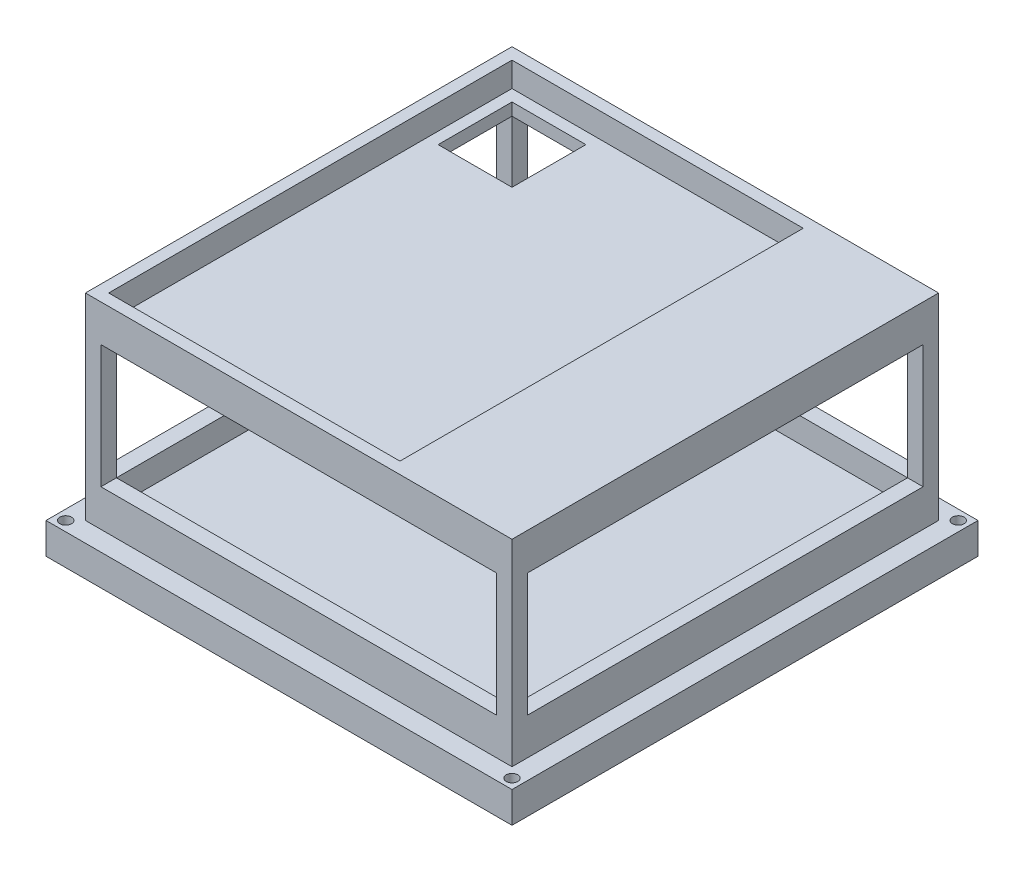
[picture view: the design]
ISO-10303-21;
HEADER;
FILE_DESCRIPTION(('STEP AP214'),'2;1');
FILE_NAME('part.step','',(''),(''),'','','');
FILE_SCHEMA(('AUTOMOTIVE_DESIGN { 1 0 10303 214 1 1 1 1 }'));
ENDSEC;
DATA;
#1=APPLICATION_CONTEXT('core data for automotive mechanical design processes');
#2=APPLICATION_PROTOCOL_DEFINITION('international standard','automotive_design',2000,#1);
#3=PRODUCT_CONTEXT('',#1,'mechanical');
#4=PRODUCT('Part','Part','',(#3));
#5=PRODUCT_RELATED_PRODUCT_CATEGORY('part','',(#4));
#6=PRODUCT_DEFINITION_FORMATION('','',#4);
#7=PRODUCT_DEFINITION_CONTEXT('part definition',#1,'design');
#8=PRODUCT_DEFINITION('design','',#6,#7);
#9=PRODUCT_DEFINITION_SHAPE('','',#8);
#10=(LENGTH_UNIT() NAMED_UNIT(*) SI_UNIT(.MILLI.,.METRE.));
#11=(NAMED_UNIT(*) PLANE_ANGLE_UNIT() SI_UNIT($,.RADIAN.));
#12=(NAMED_UNIT(*) SI_UNIT($,.STERADIAN.) SOLID_ANGLE_UNIT());
#13=UNCERTAINTY_MEASURE_WITH_UNIT(LENGTH_MEASURE(1.E-05),#10,'distance_accuracy_value','');
#14=(GEOMETRIC_REPRESENTATION_CONTEXT(3) GLOBAL_UNCERTAINTY_ASSIGNED_CONTEXT((#13)) GLOBAL_UNIT_ASSIGNED_CONTEXT((#10,
#11,#12)) REPRESENTATION_CONTEXT('',''));
#15=CARTESIAN_POINT('',(0.,0.,0.));
#16=DIRECTION('',(0.,0.,1.));
#17=DIRECTION('',(1.,0.,0.));
#18=AXIS2_PLACEMENT_3D('',#15,#16,#17);
#19=CARTESIAN_POINT('',(0.,9.525,0.));
#20=DIRECTION('',(0.,-1.,0.));
#21=DIRECTION('',(0.,0.,-1.));
#22=AXIS2_PLACEMENT_3D('',#19,#20,#21);
#23=PLANE('',#22);
#24=DIRECTION('',(0.,0.,1.));
#25=VECTOR('',#24,1.);
#26=CARTESIAN_POINT('',(51.,9.525,-55.));
#27=LINE('',#26,#25);
#28=CARTESIAN_POINT('',(51.,9.525,-55.));
#29=VERTEX_POINT('',#28);
#30=CARTESIAN_POINT('',(51.,9.525,-51.));
#31=VERTEX_POINT('',#30);
#32=EDGE_CURVE('E333',#29,#31,#27,.T.);
#33=ORIENTED_EDGE('',*,*,#32,.F.);
#34=DIRECTION('',(-1.,0.,0.));
#35=VECTOR('',#34,1.);
#36=CARTESIAN_POINT('',(-55.,9.525,-55.));
#37=LINE('',#36,#35);
#38=CARTESIAN_POINT('',(-51.,9.525,-55.));
#39=VERTEX_POINT('',#38);
#40=EDGE_CURVE('E497',#29,#39,#37,.T.);
#41=ORIENTED_EDGE('',*,*,#40,.T.);
#42=DIRECTION('',(0.,0.,-1.));
#43=VECTOR('',#42,1.);
#44=CARTESIAN_POINT('',(-51.,9.525,-55.));
#45=LINE('',#44,#43);
#46=CARTESIAN_POINT('',(-51.,9.525,-51.));
#47=VERTEX_POINT('',#46);
#48=EDGE_CURVE('E388',#47,#39,#45,.T.);
#49=ORIENTED_EDGE('',*,*,#48,.F.);
#50=DIRECTION('',(-1.,0.,0.));
#51=VECTOR('',#50,1.);
#52=CARTESIAN_POINT('',(-51.,9.525,-51.));
#53=LINE('',#52,#51);
#54=EDGE_CURVE('E421',#31,#47,#53,.T.);
#55=ORIENTED_EDGE('',*,*,#54,.F.);
#56=EDGE_LOOP('',(#33,#41,#49,#55));
#57=FACE_BOUND('',#56,.T.);
#58=ADVANCED_FACE('F39',(#57),#23,.F.);
#59=DIRECTION('',(1.,0.,0.));
#60=VECTOR('',#59,1.);
#61=CARTESIAN_POINT('',(55.,9.525,-51.));
#62=LINE('',#61,#60);
#63=CARTESIAN_POINT('',(55.,9.525,-51.));
#64=VERTEX_POINT('',#63);
#65=EDGE_CURVE('E330',#31,#64,#62,.T.);
#66=ORIENTED_EDGE('',*,*,#65,.F.);
#67=DIRECTION('',(0.,0.,-1.));
#68=VECTOR('',#67,1.);
#69=CARTESIAN_POINT('',(51.,9.525,51.));
#70=LINE('',#69,#68);
#71=CARTESIAN_POINT('',(51.,9.525,51.));
#72=VERTEX_POINT('',#71);
#73=EDGE_CURVE('E404',#72,#31,#70,.T.);
#74=ORIENTED_EDGE('',*,*,#73,.F.);
#75=DIRECTION('',(-1.,0.,0.));
#76=VECTOR('',#75,1.);
#77=CARTESIAN_POINT('',(55.,9.525,51.));
#78=LINE('',#77,#76);
#79=CARTESIAN_POINT('',(55.,9.525,51.));
#80=VERTEX_POINT('',#79);
#81=EDGE_CURVE('E354',#80,#72,#78,.T.);
#82=ORIENTED_EDGE('',*,*,#81,.F.);
#83=DIRECTION('',(0.,0.,-1.));
#84=VECTOR('',#83,1.);
#85=CARTESIAN_POINT('',(55.,9.525,55.));
#86=LINE('',#85,#84);
#87=EDGE_CURVE('E495',#80,#64,#86,.T.);
#88=ORIENTED_EDGE('',*,*,#87,.T.);
#89=EDGE_LOOP('',(#66,#74,#82,#88));
#90=FACE_BOUND('',#89,.T.);
#91=ADVANCED_FACE('F552',(#90),#23,.F.);
#92=DIRECTION('',(0.,0.,1.));
#93=VECTOR('',#92,1.);
#94=CARTESIAN_POINT('',(51.,9.525,55.));
#95=LINE('',#94,#93);
#96=CARTESIAN_POINT('',(51.,9.525,55.));
#97=VERTEX_POINT('',#96);
#98=EDGE_CURVE('E351',#72,#97,#95,.T.);
#99=ORIENTED_EDGE('',*,*,#98,.F.);
#100=DIRECTION('',(1.,0.,0.));
#101=VECTOR('',#100,1.);
#102=CARTESIAN_POINT('',(-51.,9.525,51.));
#103=LINE('',#102,#101);
#104=CARTESIAN_POINT('',(-51.,9.525,51.));
#105=VERTEX_POINT('',#104);
#106=EDGE_CURVE('E409',#105,#72,#103,.T.);
#107=ORIENTED_EDGE('',*,*,#106,.F.);
#108=DIRECTION('',(0.,0.,-1.));
#109=VECTOR('',#108,1.);
#110=CARTESIAN_POINT('',(-51.,9.525,55.));
#111=LINE('',#110,#109);
#112=CARTESIAN_POINT('',(-51.,9.525,55.));
#113=VERTEX_POINT('',#112);
#114=EDGE_CURVE('E375',#113,#105,#111,.T.);
#115=ORIENTED_EDGE('',*,*,#114,.F.);
#116=DIRECTION('',(1.,0.,0.));
#117=VECTOR('',#116,1.);
#118=CARTESIAN_POINT('',(-55.,9.525,55.));
#119=LINE('',#118,#117);
#120=EDGE_CURVE('E502',#113,#97,#119,.T.);
#121=ORIENTED_EDGE('',*,*,#120,.T.);
#122=EDGE_LOOP('',(#99,#107,#115,#121));
#123=FACE_BOUND('',#122,.T.);
#124=ADVANCED_FACE('F559',(#123),#23,.F.);
#125=DIRECTION('',(-1.,0.,0.));
#126=VECTOR('',#125,1.);
#127=CARTESIAN_POINT('',(-55.,9.525,51.));
#128=LINE('',#127,#126);
#129=CARTESIAN_POINT('',(-55.,9.525,51.));
#130=VERTEX_POINT('',#129);
#131=EDGE_CURVE('E372',#105,#130,#128,.T.);
#132=ORIENTED_EDGE('',*,*,#131,.F.);
#133=DIRECTION('',(0.,0.,1.));
#134=VECTOR('',#133,1.);
#135=CARTESIAN_POINT('',(-51.,9.525,51.));
#136=LINE('',#135,#134);
#137=EDGE_CURVE('E424',#47,#105,#136,.T.);
#138=ORIENTED_EDGE('',*,*,#137,.F.);
#139=DIRECTION('',(1.,0.,0.));
#140=VECTOR('',#139,1.);
#141=CARTESIAN_POINT('',(-55.,9.525,-51.));
#142=LINE('',#141,#140);
#143=CARTESIAN_POINT('',(-55.,9.525,-51.));
#144=VERTEX_POINT('',#143);
#145=EDGE_CURVE('E379',#144,#47,#142,.T.);
#146=ORIENTED_EDGE('',*,*,#145,.F.);
#147=DIRECTION('',(0.,0.,1.));
#148=VECTOR('',#147,1.);
#149=CARTESIAN_POINT('',(-55.,9.525,55.));
#150=LINE('',#149,#148);
#151=EDGE_CURVE('E500',#144,#130,#150,.T.);
#152=ORIENTED_EDGE('',*,*,#151,.T.);
#153=EDGE_LOOP('',(#132,#138,#146,#152));
#154=FACE_BOUND('',#153,.T.);
#155=ADVANCED_FACE('F554',(#154),#23,.F.);
#156=CARTESIAN_POINT('',(55.,9.525,55.));
#157=DIRECTION('',(-1.,0.,0.));
#158=DIRECTION('',(0.,0.,1.));
#159=AXIS2_PLACEMENT_3D('',#156,#157,#158);
#160=PLANE('',#159);
#161=DIRECTION('',(0.,-1.,0.));
#162=VECTOR('',#161,1.);
#163=CARTESIAN_POINT('',(55.,41.275,51.));
#164=LINE('',#163,#162);
#165=CARTESIAN_POINT('',(55.,41.275,51.));
#166=VERTEX_POINT('',#165);
#167=EDGE_CURVE('E337',#166,#80,#164,.T.);
#168=ORIENTED_EDGE('',*,*,#167,.F.);
#169=DIRECTION('',(0.,0.,-1.));
#170=VECTOR('',#169,1.);
#171=CARTESIAN_POINT('',(55.,41.275,-55.));
#172=LINE('',#171,#170);
#173=CARTESIAN_POINT('',(55.,41.275,-51.));
#174=VERTEX_POINT('',#173);
#175=EDGE_CURVE('E316',#166,#174,#172,.T.);
#176=ORIENTED_EDGE('',*,*,#175,.T.);
#177=DIRECTION('',(0.,-1.,0.));
#178=VECTOR('',#177,1.);
#179=CARTESIAN_POINT('',(55.,41.275,-51.));
#180=LINE('',#179,#178);
#181=EDGE_CURVE('E326',#174,#64,#180,.T.);
#182=ORIENTED_EDGE('',*,*,#181,.T.);
#183=ORIENTED_EDGE('',*,*,#87,.F.);
#184=EDGE_LOOP('',(#168,#176,#182,#183));
#185=FACE_BOUND('',#184,.T.);
#186=DIRECTION('',(0.,0.,-1.));
#187=VECTOR('',#186,1.);
#188=CARTESIAN_POINT('',(55.,0.,55.));
#189=LINE('',#188,#187);
#190=CARTESIAN_POINT('',(55.,0.,55.));
#191=VERTEX_POINT('',#190);
#192=CARTESIAN_POINT('',(55.,0.,-55.));
#193=VERTEX_POINT('',#192);
#194=EDGE_CURVE('E494',#191,#193,#189,.T.);
#195=ORIENTED_EDGE('',*,*,#194,.T.);
#196=DIRECTION('',(0.,-1.,0.));
#197=VECTOR('',#196,1.);
#198=CARTESIAN_POINT('',(55.,9.525,-55.));
#199=LINE('',#198,#197);
#200=CARTESIAN_POINT('',(55.,50.8,-55.));
#201=VERTEX_POINT('',#200);
#202=EDGE_CURVE('E11',#201,#193,#199,.T.);
#203=ORIENTED_EDGE('',*,*,#202,.F.);
#204=DIRECTION('',(0.,0.,-1.));
#205=VECTOR('',#204,1.);
#206=CARTESIAN_POINT('',(55.,50.8,-55.));
#207=LINE('',#206,#205);
#208=CARTESIAN_POINT('',(55.,50.8,55.));
#209=VERTEX_POINT('',#208);
#210=EDGE_CURVE('E304',#209,#201,#207,.T.);
#211=ORIENTED_EDGE('',*,*,#210,.F.);
#212=DIRECTION('',(0.,-1.,0.));
#213=VECTOR('',#212,1.);
#214=CARTESIAN_POINT('',(55.,9.525,55.));
#215=LINE('',#214,#213);
#216=EDGE_CURVE('E504',#209,#191,#215,.T.);
#217=ORIENTED_EDGE('',*,*,#216,.T.);
#218=EDGE_LOOP('',(#195,#203,#211,#217));
#219=FACE_BOUND('',#218,.T.);
#220=ADVANCED_FACE('F41',(#185,#219),#160,.F.);
#221=CARTESIAN_POINT('',(-55.,9.525,-55.));
#222=DIRECTION('',(0.,0.,1.));
#223=DIRECTION('',(1.,0.,0.));
#224=AXIS2_PLACEMENT_3D('',#221,#222,#223);
#225=PLANE('',#224);
#226=DIRECTION('',(0.,-1.,0.));
#227=VECTOR('',#226,1.);
#228=CARTESIAN_POINT('',(-55.,9.525,-55.));
#229=LINE('',#228,#227);
#230=CARTESIAN_POINT('',(-55.,50.8,-55.));
#231=VERTEX_POINT('',#230);
#232=CARTESIAN_POINT('',(-55.,0.,-55.));
#233=VERTEX_POINT('',#232);
#234=EDGE_CURVE('E47',#231,#233,#229,.T.);
#235=ORIENTED_EDGE('',*,*,#234,.F.);
#236=DIRECTION('',(-1.,0.,0.));
#237=VECTOR('',#236,1.);
#238=CARTESIAN_POINT('',(-55.,50.8,-55.));
#239=LINE('',#238,#237);
#240=EDGE_CURVE('E307',#201,#231,#239,.T.);
#241=ORIENTED_EDGE('',*,*,#240,.F.);
#242=ORIENTED_EDGE('',*,*,#202,.T.);
#243=DIRECTION('',(-1.,0.,0.));
#244=VECTOR('',#243,1.);
#245=CARTESIAN_POINT('',(-55.,0.,-55.));
#246=LINE('',#245,#244);
#247=EDGE_CURVE('E507',#193,#233,#246,.T.);
#248=ORIENTED_EDGE('',*,*,#247,.T.);
#249=EDGE_LOOP('',(#235,#241,#242,#248));
#250=FACE_BOUND('',#249,.T.);
#251=DIRECTION('',(-1.,0.,0.));
#252=VECTOR('',#251,1.);
#253=CARTESIAN_POINT('',(-55.,41.275,-55.));
#254=LINE('',#253,#252);
#255=CARTESIAN_POINT('',(51.,41.275,-55.));
#256=VERTEX_POINT('',#255);
#257=CARTESIAN_POINT('',(-51.,41.275,-55.));
#258=VERTEX_POINT('',#257);
#259=EDGE_CURVE('E301',#256,#258,#254,.T.);
#260=ORIENTED_EDGE('',*,*,#259,.T.);
#261=DIRECTION('',(0.,-1.,0.));
#262=VECTOR('',#261,1.);
#263=CARTESIAN_POINT('',(-51.,41.275,-55.));
#264=LINE('',#263,#262);
#265=EDGE_CURVE('E391',#258,#39,#264,.T.);
#266=ORIENTED_EDGE('',*,*,#265,.T.);
#267=ORIENTED_EDGE('',*,*,#40,.F.);
#268=DIRECTION('',(0.,-1.,0.));
#269=VECTOR('',#268,1.);
#270=CARTESIAN_POINT('',(51.,41.275,-55.));
#271=LINE('',#270,#269);
#272=EDGE_CURVE('E310',#256,#29,#271,.T.);
#273=ORIENTED_EDGE('',*,*,#272,.F.);
#274=EDGE_LOOP('',(#260,#266,#267,#273));
#275=FACE_BOUND('',#274,.T.);
#276=ADVANCED_FACE('F525',(#250,#275),#225,.F.);
#277=CARTESIAN_POINT('',(-55.,9.525,55.));
#278=DIRECTION('',(1.,0.,0.));
#279=DIRECTION('',(0.,0.,-1.));
#280=AXIS2_PLACEMENT_3D('',#277,#278,#279);
#281=PLANE('',#280);
#282=DIRECTION('',(0.,-1.,0.));
#283=VECTOR('',#282,1.);
#284=CARTESIAN_POINT('',(-55.,41.275,-51.));
#285=LINE('',#284,#283);
#286=CARTESIAN_POINT('',(-55.,41.275,-51.));
#287=VERTEX_POINT('',#286);
#288=EDGE_CURVE('E401',#287,#144,#285,.T.);
#289=ORIENTED_EDGE('',*,*,#288,.F.);
#290=DIRECTION('',(0.,0.,1.));
#291=VECTOR('',#290,1.);
#292=CARTESIAN_POINT('',(-55.,41.275,-55.));
#293=LINE('',#292,#291);
#294=CARTESIAN_POINT('',(-55.,41.275,51.));
#295=VERTEX_POINT('',#294);
#296=EDGE_CURVE('E290',#287,#295,#293,.T.);
#297=ORIENTED_EDGE('',*,*,#296,.T.);
#298=DIRECTION('',(0.,-1.,0.));
#299=VECTOR('',#298,1.);
#300=CARTESIAN_POINT('',(-55.,41.275,51.));
#301=LINE('',#300,#299);
#302=EDGE_CURVE('E368',#295,#130,#301,.T.);
#303=ORIENTED_EDGE('',*,*,#302,.T.);
#304=ORIENTED_EDGE('',*,*,#151,.F.);
#305=EDGE_LOOP('',(#289,#297,#303,#304));
#306=FACE_BOUND('',#305,.T.);
#307=DIRECTION('',(0.,0.,1.));
#308=VECTOR('',#307,1.);
#309=CARTESIAN_POINT('',(-55.,0.,55.));
#310=LINE('',#309,#308);
#311=CARTESIAN_POINT('',(-55.,0.,55.));
#312=VERTEX_POINT('',#311);
#313=EDGE_CURVE('E510',#233,#312,#310,.T.);
#314=ORIENTED_EDGE('',*,*,#313,.T.);
#315=DIRECTION('',(0.,-1.,0.));
#316=VECTOR('',#315,1.);
#317=CARTESIAN_POINT('',(-55.,9.525,55.));
#318=LINE('',#317,#316);
#319=CARTESIAN_POINT('',(-55.,50.8,55.));
#320=VERTEX_POINT('',#319);
#321=EDGE_CURVE('E517',#320,#312,#318,.T.);
#322=ORIENTED_EDGE('',*,*,#321,.F.);
#323=DIRECTION('',(0.,0.,1.));
#324=VECTOR('',#323,1.);
#325=CARTESIAN_POINT('',(-55.,50.8,-55.));
#326=LINE('',#325,#324);
#327=EDGE_CURVE('E297',#231,#320,#326,.T.);
#328=ORIENTED_EDGE('',*,*,#327,.F.);
#329=ORIENTED_EDGE('',*,*,#234,.T.);
#330=EDGE_LOOP('',(#314,#322,#328,#329));
#331=FACE_BOUND('',#330,.T.);
#332=ADVANCED_FACE('F522',(#306,#331),#281,.F.);
#333=CARTESIAN_POINT('',(-55.,9.525,55.));
#334=DIRECTION('',(0.,0.,-1.));
#335=DIRECTION('',(-1.,0.,0.));
#336=AXIS2_PLACEMENT_3D('',#333,#334,#335);
#337=PLANE('',#336);
#338=DIRECTION('',(0.,-1.,0.));
#339=VECTOR('',#338,1.);
#340=CARTESIAN_POINT('',(-51.,41.275,55.));
#341=LINE('',#340,#339);
#342=CARTESIAN_POINT('',(-51.,41.275,55.));
#343=VERTEX_POINT('',#342);
#344=EDGE_CURVE('E358',#343,#113,#341,.T.);
#345=ORIENTED_EDGE('',*,*,#344,.F.);
#346=DIRECTION('',(1.,0.,0.));
#347=VECTOR('',#346,1.);
#348=CARTESIAN_POINT('',(-55.,41.275,55.));
#349=LINE('',#348,#347);
#350=CARTESIAN_POINT('',(51.,41.275,55.));
#351=VERTEX_POINT('',#350);
#352=EDGE_CURVE('E313',#343,#351,#349,.T.);
#353=ORIENTED_EDGE('',*,*,#352,.T.);
#354=DIRECTION('',(0.,-1.,0.));
#355=VECTOR('',#354,1.);
#356=CARTESIAN_POINT('',(51.,41.275,55.));
#357=LINE('',#356,#355);
#358=EDGE_CURVE('E347',#351,#97,#357,.T.);
#359=ORIENTED_EDGE('',*,*,#358,.T.);
#360=ORIENTED_EDGE('',*,*,#120,.F.);
#361=EDGE_LOOP('',(#345,#353,#359,#360));
#362=FACE_BOUND('',#361,.T.);
#363=DIRECTION('',(1.,0.,0.));
#364=VECTOR('',#363,1.);
#365=CARTESIAN_POINT('',(-55.,0.,55.));
#366=LINE('',#365,#364);
#367=EDGE_CURVE('E498',#312,#191,#366,.T.);
#368=ORIENTED_EDGE('',*,*,#367,.T.);
#369=ORIENTED_EDGE('',*,*,#216,.F.);
#370=DIRECTION('',(1.,0.,0.));
#371=VECTOR('',#370,1.);
#372=CARTESIAN_POINT('',(-55.,50.8,55.));
#373=LINE('',#372,#371);
#374=EDGE_CURVE('E300',#320,#209,#373,.T.);
#375=ORIENTED_EDGE('',*,*,#374,.F.);
#376=ORIENTED_EDGE('',*,*,#321,.T.);
#377=EDGE_LOOP('',(#368,#369,#375,#376));
#378=FACE_BOUND('',#377,.T.);
#379=ADVANCED_FACE('F535',(#362,#378),#337,.F.);
#380=CARTESIAN_POINT('',(0.,0.,0.));
#381=DIRECTION('',(0.,1.,0.));
#382=DIRECTION('',(0.,0.,1.));
#383=AXIS2_PLACEMENT_3D('',#380,#381,#382);
#384=PLANE('',#383);
#385=CARTESIAN_POINT('',(-57.54,0.,57.54));
#386=DIRECTION('',(0.,1.,0.));
#387=DIRECTION('',(0.,0.,-1.));
#388=AXIS2_PLACEMENT_3D('',#385,#386,#387);
#389=CIRCLE('',#388,1.5);
#390=CARTESIAN_POINT('',(-57.54,0.,56.04));
#391=VERTEX_POINT('',#390);
#392=EDGE_CURVE('E454',#391,#391,#389,.T.);
#393=ORIENTED_EDGE('',*,*,#392,.F.);
#394=EDGE_LOOP('',(#393));
#395=FACE_BOUND('',#394,.T.);
#396=CARTESIAN_POINT('',(57.54,0.,57.54));
#397=DIRECTION('',(0.,1.,0.));
#398=DIRECTION('',(0.,0.,1.));
#399=AXIS2_PLACEMENT_3D('',#396,#397,#398);
#400=CIRCLE('',#399,1.5);
#401=CARTESIAN_POINT('',(57.54,0.,59.04));
#402=VERTEX_POINT('',#401);
#403=EDGE_CURVE('E448',#402,#402,#400,.T.);
#404=ORIENTED_EDGE('',*,*,#403,.F.);
#405=EDGE_LOOP('',(#404));
#406=FACE_BOUND('',#405,.T.);
#407=CARTESIAN_POINT('',(57.54,0.,-57.54));
#408=DIRECTION('',(0.,1.,0.));
#409=DIRECTION('',(0.,0.,-1.));
#410=AXIS2_PLACEMENT_3D('',#407,#408,#409);
#411=CIRCLE('',#410,1.5);
#412=CARTESIAN_POINT('',(57.54,0.,-59.04));
#413=VERTEX_POINT('',#412);
#414=EDGE_CURVE('E441',#413,#413,#411,.T.);
#415=ORIENTED_EDGE('',*,*,#414,.F.);
#416=EDGE_LOOP('',(#415));
#417=FACE_BOUND('',#416,.T.);
#418=CARTESIAN_POINT('',(-57.54,0.,-57.54));
#419=DIRECTION('',(0.,1.,0.));
#420=DIRECTION('',(0.,0.,1.));
#421=AXIS2_PLACEMENT_3D('',#418,#419,#420);
#422=CIRCLE('',#421,1.5);
#423=CARTESIAN_POINT('',(-57.54,0.,-56.04));
#424=VERTEX_POINT('',#423);
#425=EDGE_CURVE('E444',#424,#424,#422,.T.);
#426=ORIENTED_EDGE('',*,*,#425,.F.);
#427=EDGE_LOOP('',(#426));
#428=FACE_BOUND('',#427,.T.);
#429=DIRECTION('',(0.,0.,1.));
#430=VECTOR('',#429,1.);
#431=CARTESIAN_POINT('',(60.08,0.,-60.08));
#432=LINE('',#431,#430);
#433=CARTESIAN_POINT('',(60.08,0.,-60.08));
#434=VERTEX_POINT('',#433);
#435=CARTESIAN_POINT('',(60.08,0.,60.08));
#436=VERTEX_POINT('',#435);
#437=EDGE_CURVE('E462',#434,#436,#432,.T.);
#438=ORIENTED_EDGE('',*,*,#437,.F.);
#439=DIRECTION('',(1.,0.,0.));
#440=VECTOR('',#439,1.);
#441=CARTESIAN_POINT('',(-60.08,0.,-60.08));
#442=LINE('',#441,#440);
#443=CARTESIAN_POINT('',(-60.08,0.,-60.08));
#444=VERTEX_POINT('',#443);
#445=EDGE_CURVE('E469',#444,#434,#442,.T.);
#446=ORIENTED_EDGE('',*,*,#445,.F.);
#447=DIRECTION('',(0.,0.,-1.));
#448=VECTOR('',#447,1.);
#449=CARTESIAN_POINT('',(-60.08,0.,-60.08));
#450=LINE('',#449,#448);
#451=CARTESIAN_POINT('',(-60.08,0.,60.08));
#452=VERTEX_POINT('',#451);
#453=EDGE_CURVE('E480',#452,#444,#450,.T.);
#454=ORIENTED_EDGE('',*,*,#453,.F.);
#455=DIRECTION('',(-1.,0.,0.));
#456=VECTOR('',#455,1.);
#457=CARTESIAN_POINT('',(-60.08,0.,60.08));
#458=LINE('',#457,#456);
#459=EDGE_CURVE('E478',#436,#452,#458,.T.);
#460=ORIENTED_EDGE('',*,*,#459,.F.);
#461=EDGE_LOOP('',(#438,#446,#454,#460));
#462=FACE_BOUND('',#461,.T.);
#463=ORIENTED_EDGE('',*,*,#194,.F.);
#464=ORIENTED_EDGE('',*,*,#367,.F.);
#465=ORIENTED_EDGE('',*,*,#313,.F.);
#466=ORIENTED_EDGE('',*,*,#247,.F.);
#467=EDGE_LOOP('',(#463,#464,#465,#466));
#468=FACE_BOUND('',#467,.T.);
#469=ADVANCED_FACE('F533',(#395,#406,#417,#428,#462,#468),#384,.T.);
#470=CARTESIAN_POINT('',(60.08,-8.,-60.08));
#471=DIRECTION('',(-1.,0.,0.));
#472=DIRECTION('',(0.,0.,1.));
#473=AXIS2_PLACEMENT_3D('',#470,#471,#472);
#474=PLANE('',#473);
#475=ORIENTED_EDGE('',*,*,#437,.T.);
#476=DIRECTION('',(0.,1.,0.));
#477=VECTOR('',#476,1.);
#478=CARTESIAN_POINT('',(60.08,-8.,60.08));
#479=LINE('',#478,#477);
#480=CARTESIAN_POINT('',(60.08,-8.,60.08));
#481=VERTEX_POINT('',#480);
#482=EDGE_CURVE('E491',#481,#436,#479,.T.);
#483=ORIENTED_EDGE('',*,*,#482,.F.);
#484=DIRECTION('',(0.,0.,1.));
#485=VECTOR('',#484,1.);
#486=CARTESIAN_POINT('',(60.08,-8.,-60.08));
#487=LINE('',#486,#485);
#488=CARTESIAN_POINT('',(60.08,-8.,-60.08));
#489=VERTEX_POINT('',#488);
#490=EDGE_CURVE('E465',#489,#481,#487,.T.);
#491=ORIENTED_EDGE('',*,*,#490,.F.);
#492=DIRECTION('',(0.,1.,0.));
#493=VECTOR('',#492,1.);
#494=CARTESIAN_POINT('',(60.08,-8.,-60.08));
#495=LINE('',#494,#493);
#496=EDGE_CURVE('E475',#489,#434,#495,.T.);
#497=ORIENTED_EDGE('',*,*,#496,.T.);
#498=EDGE_LOOP('',(#475,#483,#491,#497));
#499=FACE_BOUND('',#498,.T.);
#500=ADVANCED_FACE('F544',(#499),#474,.F.);
#501=CARTESIAN_POINT('',(-60.08,-8.,60.08));
#502=DIRECTION('',(0.,0.,-1.));
#503=DIRECTION('',(-1.,0.,0.));
#504=AXIS2_PLACEMENT_3D('',#501,#502,#503);
#505=PLANE('',#504);
#506=ORIENTED_EDGE('',*,*,#459,.T.);
#507=DIRECTION('',(0.,1.,0.));
#508=VECTOR('',#507,1.);
#509=CARTESIAN_POINT('',(-60.08,-8.,60.08));
#510=LINE('',#509,#508);
#511=CARTESIAN_POINT('',(-60.08,-8.,60.08));
#512=VERTEX_POINT('',#511);
#513=EDGE_CURVE('E488',#512,#452,#510,.T.);
#514=ORIENTED_EDGE('',*,*,#513,.F.);
#515=DIRECTION('',(-1.,0.,0.));
#516=VECTOR('',#515,1.);
#517=CARTESIAN_POINT('',(-60.08,-8.,60.08));
#518=LINE('',#517,#516);
#519=EDGE_CURVE('E468',#481,#512,#518,.T.);
#520=ORIENTED_EDGE('',*,*,#519,.F.);
#521=ORIENTED_EDGE('',*,*,#482,.T.);
#522=EDGE_LOOP('',(#506,#514,#520,#521));
#523=FACE_BOUND('',#522,.T.);
#524=ADVANCED_FACE('F657',(#523),#505,.F.);
#525=CARTESIAN_POINT('',(-60.08,-8.,-60.08));
#526=DIRECTION('',(1.,0.,0.));
#527=DIRECTION('',(0.,0.,-1.));
#528=AXIS2_PLACEMENT_3D('',#525,#526,#527);
#529=PLANE('',#528);
#530=ORIENTED_EDGE('',*,*,#453,.T.);
#531=DIRECTION('',(0.,1.,0.));
#532=VECTOR('',#531,1.);
#533=CARTESIAN_POINT('',(-60.08,-8.,-60.08));
#534=LINE('',#533,#532);
#535=CARTESIAN_POINT('',(-60.08,-8.,-60.08));
#536=VERTEX_POINT('',#535);
#537=EDGE_CURVE('E485',#536,#444,#534,.T.);
#538=ORIENTED_EDGE('',*,*,#537,.F.);
#539=DIRECTION('',(0.,0.,-1.));
#540=VECTOR('',#539,1.);
#541=CARTESIAN_POINT('',(-60.08,-8.,-60.08));
#542=LINE('',#541,#540);
#543=EDGE_CURVE('E471',#512,#536,#542,.T.);
#544=ORIENTED_EDGE('',*,*,#543,.F.);
#545=ORIENTED_EDGE('',*,*,#513,.T.);
#546=EDGE_LOOP('',(#530,#538,#544,#545));
#547=FACE_BOUND('',#546,.T.);
#548=ADVANCED_FACE('F653',(#547),#529,.F.);
#549=CARTESIAN_POINT('',(-60.08,-8.,-60.08));
#550=DIRECTION('',(0.,0.,1.));
#551=DIRECTION('',(1.,0.,0.));
#552=AXIS2_PLACEMENT_3D('',#549,#550,#551);
#553=PLANE('',#552);
#554=ORIENTED_EDGE('',*,*,#445,.T.);
#555=ORIENTED_EDGE('',*,*,#496,.F.);
#556=DIRECTION('',(1.,0.,0.));
#557=VECTOR('',#556,1.);
#558=CARTESIAN_POINT('',(-60.08,-8.,-60.08));
#559=LINE('',#558,#557);
#560=EDGE_CURVE('E473',#536,#489,#559,.T.);
#561=ORIENTED_EDGE('',*,*,#560,.F.);
#562=ORIENTED_EDGE('',*,*,#537,.T.);
#563=EDGE_LOOP('',(#554,#555,#561,#562));
#564=FACE_BOUND('',#563,.T.);
#565=ADVANCED_FACE('F648',(#564),#553,.F.);
#566=CARTESIAN_POINT('',(0.,-8.,0.));
#567=DIRECTION('',(0.,1.,0.));
#568=DIRECTION('',(0.,0.,1.));
#569=AXIS2_PLACEMENT_3D('',#566,#567,#568);
#570=PLANE('',#569);
#571=CARTESIAN_POINT('',(-57.54,-8.,57.54));
#572=DIRECTION('',(0.,1.,0.));
#573=DIRECTION('',(0.,0.,-1.));
#574=AXIS2_PLACEMENT_3D('',#571,#572,#573);
#575=CIRCLE('',#574,1.5);
#576=CARTESIAN_POINT('',(-57.54,-8.,56.04));
#577=VERTEX_POINT('',#576);
#578=EDGE_CURVE('E432',#577,#577,#575,.T.);
#579=ORIENTED_EDGE('',*,*,#578,.T.);
#580=EDGE_LOOP('',(#579));
#581=FACE_BOUND('',#580,.T.);
#582=CARTESIAN_POINT('',(57.54,-8.,57.54));
#583=DIRECTION('',(0.,1.,0.));
#584=DIRECTION('',(0.,0.,1.));
#585=AXIS2_PLACEMENT_3D('',#582,#583,#584);
#586=CIRCLE('',#585,1.5);
#587=CARTESIAN_POINT('',(57.54,-8.,59.04));
#588=VERTEX_POINT('',#587);
#589=EDGE_CURVE('E451',#588,#588,#586,.T.);
#590=ORIENTED_EDGE('',*,*,#589,.T.);
#591=EDGE_LOOP('',(#590));
#592=FACE_BOUND('',#591,.T.);
#593=CARTESIAN_POINT('',(57.54,-8.,-57.54));
#594=DIRECTION('',(0.,1.,0.));
#595=DIRECTION('',(0.,0.,-1.));
#596=AXIS2_PLACEMENT_3D('',#593,#594,#595);
#597=CIRCLE('',#596,1.5);
#598=CARTESIAN_POINT('',(57.54,-8.,-59.04));
#599=VERTEX_POINT('',#598);
#600=EDGE_CURVE('E445',#599,#599,#597,.T.);
#601=ORIENTED_EDGE('',*,*,#600,.T.);
#602=EDGE_LOOP('',(#601));
#603=FACE_BOUND('',#602,.T.);
#604=CARTESIAN_POINT('',(-57.54,-8.,-57.54));
#605=DIRECTION('',(0.,1.,0.));
#606=DIRECTION('',(0.,0.,1.));
#607=AXIS2_PLACEMENT_3D('',#604,#605,#606);
#608=CIRCLE('',#607,1.5);
#609=CARTESIAN_POINT('',(-57.54,-8.,-56.04));
#610=VERTEX_POINT('',#609);
#611=EDGE_CURVE('E459',#610,#610,#608,.T.);
#612=ORIENTED_EDGE('',*,*,#611,.T.);
#613=EDGE_LOOP('',(#612));
#614=FACE_BOUND('',#613,.T.);
#615=ORIENTED_EDGE('',*,*,#490,.T.);
#616=ORIENTED_EDGE('',*,*,#519,.T.);
#617=ORIENTED_EDGE('',*,*,#543,.T.);
#618=ORIENTED_EDGE('',*,*,#560,.T.);
#619=EDGE_LOOP('',(#615,#616,#617,#618));
#620=FACE_BOUND('',#619,.T.);
#621=ADVANCED_FACE('F645',(#581,#592,#603,#614,#620),#570,.F.);
#622=CARTESIAN_POINT('',(-57.54,-8.,-57.54));
#623=DIRECTION('',(0.,1.,0.));
#624=DIRECTION('',(0.,0.,1.));
#625=AXIS2_PLACEMENT_3D('',#622,#623,#624);
#626=CYLINDRICAL_SURFACE('',#625,1.5);
#627=ORIENTED_EDGE('',*,*,#611,.F.);
#628=EDGE_LOOP('',(#627));
#629=FACE_BOUND('',#628,.T.);
#630=ORIENTED_EDGE('',*,*,#425,.T.);
#631=EDGE_LOOP('',(#630));
#632=FACE_BOUND('',#631,.T.);
#633=ADVANCED_FACE('F636',(#629,#632),#626,.F.);
#634=CARTESIAN_POINT('',(57.54,-8.,-57.54));
#635=DIRECTION('',(0.,1.,0.));
#636=DIRECTION('',(0.,0.,1.));
#637=AXIS2_PLACEMENT_3D('',#634,#635,#636);
#638=CYLINDRICAL_SURFACE('',#637,1.5);
#639=ORIENTED_EDGE('',*,*,#600,.F.);
#640=EDGE_LOOP('',(#639));
#641=FACE_BOUND('',#640,.T.);
#642=ORIENTED_EDGE('',*,*,#414,.T.);
#643=EDGE_LOOP('',(#642));
#644=FACE_BOUND('',#643,.T.);
#645=ADVANCED_FACE('F632',(#641,#644),#638,.F.);
#646=CARTESIAN_POINT('',(57.54,-8.,57.54));
#647=DIRECTION('',(0.,1.,0.));
#648=DIRECTION('',(0.,0.,1.));
#649=AXIS2_PLACEMENT_3D('',#646,#647,#648);
#650=CYLINDRICAL_SURFACE('',#649,1.5);
#651=ORIENTED_EDGE('',*,*,#589,.F.);
#652=EDGE_LOOP('',(#651));
#653=FACE_BOUND('',#652,.T.);
#654=ORIENTED_EDGE('',*,*,#403,.T.);
#655=EDGE_LOOP('',(#654));
#656=FACE_BOUND('',#655,.T.);
#657=ADVANCED_FACE('F635',(#653,#656),#650,.F.);
#658=CARTESIAN_POINT('',(-57.54,-8.,57.54));
#659=DIRECTION('',(0.,1.,0.));
#660=DIRECTION('',(0.,0.,1.));
#661=AXIS2_PLACEMENT_3D('',#658,#659,#660);
#662=CYLINDRICAL_SURFACE('',#661,1.5);
#663=ORIENTED_EDGE('',*,*,#578,.F.);
#664=EDGE_LOOP('',(#663));
#665=FACE_BOUND('',#664,.T.);
#666=ORIENTED_EDGE('',*,*,#392,.T.);
#667=EDGE_LOOP('',(#666));
#668=FACE_BOUND('',#667,.T.);
#669=ADVANCED_FACE('F631',(#665,#668),#662,.F.);
#670=CARTESIAN_POINT('',(51.,3.175,51.));
#671=DIRECTION('',(1.,0.,0.));
#672=DIRECTION('',(0.,0.,-1.));
#673=AXIS2_PLACEMENT_3D('',#670,#671,#672);
#674=PLANE('',#673);
#675=ORIENTED_EDGE('',*,*,#73,.T.);
#676=DIRECTION('',(0.,1.,0.));
#677=VECTOR('',#676,1.);
#678=CARTESIAN_POINT('',(51.,3.175,-51.));
#679=LINE('',#678,#677);
#680=CARTESIAN_POINT('',(51.,3.175,-51.));
#681=VERTEX_POINT('',#680);
#682=EDGE_CURVE('E418',#681,#31,#679,.T.);
#683=ORIENTED_EDGE('',*,*,#682,.F.);
#684=DIRECTION('',(0.,0.,-1.));
#685=VECTOR('',#684,1.);
#686=CARTESIAN_POINT('',(51.,3.175,51.));
#687=LINE('',#686,#685);
#688=CARTESIAN_POINT('',(51.,3.175,51.));
#689=VERTEX_POINT('',#688);
#690=EDGE_CURVE('E405',#689,#681,#687,.T.);
#691=ORIENTED_EDGE('',*,*,#690,.F.);
#692=DIRECTION('',(0.,1.,0.));
#693=VECTOR('',#692,1.);
#694=CARTESIAN_POINT('',(51.,3.175,51.));
#695=LINE('',#694,#693);
#696=EDGE_CURVE('E429',#689,#72,#695,.T.);
#697=ORIENTED_EDGE('',*,*,#696,.T.);
#698=EDGE_LOOP('',(#675,#683,#691,#697));
#699=FACE_BOUND('',#698,.T.);
#700=ADVANCED_FACE('F611',(#699),#674,.F.);
#701=CARTESIAN_POINT('',(-51.,3.175,51.));
#702=DIRECTION('',(0.,0.,1.));
#703=DIRECTION('',(1.,0.,0.));
#704=AXIS2_PLACEMENT_3D('',#701,#702,#703);
#705=PLANE('',#704);
#706=ORIENTED_EDGE('',*,*,#106,.T.);
#707=ORIENTED_EDGE('',*,*,#696,.F.);
#708=DIRECTION('',(1.,0.,0.));
#709=VECTOR('',#708,1.);
#710=CARTESIAN_POINT('',(-51.,3.175,51.));
#711=LINE('',#710,#709);
#712=CARTESIAN_POINT('',(-51.,3.175,51.));
#713=VERTEX_POINT('',#712);
#714=EDGE_CURVE('E415',#713,#689,#711,.T.);
#715=ORIENTED_EDGE('',*,*,#714,.F.);
#716=DIRECTION('',(0.,1.,0.));
#717=VECTOR('',#716,1.);
#718=CARTESIAN_POINT('',(-51.,3.175,51.));
#719=LINE('',#718,#717);
#720=EDGE_CURVE('E433',#713,#105,#719,.T.);
#721=ORIENTED_EDGE('',*,*,#720,.T.);
#722=EDGE_LOOP('',(#706,#707,#715,#721));
#723=FACE_BOUND('',#722,.T.);
#724=ADVANCED_FACE('F576',(#723),#705,.F.);
#725=CARTESIAN_POINT('',(-51.,3.175,51.));
#726=DIRECTION('',(-1.,0.,0.));
#727=DIRECTION('',(0.,0.,1.));
#728=AXIS2_PLACEMENT_3D('',#725,#726,#727);
#729=PLANE('',#728);
#730=ORIENTED_EDGE('',*,*,#137,.T.);
#731=ORIENTED_EDGE('',*,*,#720,.F.);
#732=DIRECTION('',(0.,0.,1.));
#733=VECTOR('',#732,1.);
#734=CARTESIAN_POINT('',(-51.,3.175,51.));
#735=LINE('',#734,#733);
#736=CARTESIAN_POINT('',(-51.,3.175,-51.));
#737=VERTEX_POINT('',#736);
#738=EDGE_CURVE('E412',#737,#713,#735,.T.);
#739=ORIENTED_EDGE('',*,*,#738,.F.);
#740=DIRECTION('',(0.,1.,0.));
#741=VECTOR('',#740,1.);
#742=CARTESIAN_POINT('',(-51.,3.175,-51.));
#743=LINE('',#742,#741);
#744=EDGE_CURVE('E436',#737,#47,#743,.T.);
#745=ORIENTED_EDGE('',*,*,#744,.T.);
#746=EDGE_LOOP('',(#730,#731,#739,#745));
#747=FACE_BOUND('',#746,.T.);
#748=ADVANCED_FACE('F581',(#747),#729,.F.);
#749=CARTESIAN_POINT('',(-51.,3.175,-51.));
#750=DIRECTION('',(0.,0.,-1.));
#751=DIRECTION('',(-1.,0.,0.));
#752=AXIS2_PLACEMENT_3D('',#749,#750,#751);
#753=PLANE('',#752);
#754=ORIENTED_EDGE('',*,*,#54,.T.);
#755=ORIENTED_EDGE('',*,*,#744,.F.);
#756=DIRECTION('',(-1.,0.,0.));
#757=VECTOR('',#756,1.);
#758=CARTESIAN_POINT('',(-51.,3.175,-51.));
#759=LINE('',#758,#757);
#760=EDGE_CURVE('E408',#681,#737,#759,.T.);
#761=ORIENTED_EDGE('',*,*,#760,.F.);
#762=ORIENTED_EDGE('',*,*,#682,.T.);
#763=EDGE_LOOP('',(#754,#755,#761,#762));
#764=FACE_BOUND('',#763,.T.);
#765=ADVANCED_FACE('F607',(#764),#753,.F.);
#766=CARTESIAN_POINT('',(0.,3.175,0.));
#767=DIRECTION('',(0.,-1.,0.));
#768=DIRECTION('',(0.,0.,-1.));
#769=AXIS2_PLACEMENT_3D('',#766,#767,#768);
#770=PLANE('',#769);
#771=ORIENTED_EDGE('',*,*,#690,.T.);
#772=ORIENTED_EDGE('',*,*,#760,.T.);
#773=ORIENTED_EDGE('',*,*,#738,.T.);
#774=ORIENTED_EDGE('',*,*,#714,.T.);
#775=EDGE_LOOP('',(#771,#772,#773,#774));
#776=FACE_BOUND('',#775,.T.);
#777=ADVANCED_FACE('F613',(#776),#770,.F.);
#778=CARTESIAN_POINT('',(-55.,41.275,-51.));
#779=DIRECTION('',(0.,0.,-1.));
#780=DIRECTION('',(-1.,0.,0.));
#781=AXIS2_PLACEMENT_3D('',#778,#779,#780);
#782=PLANE('',#781);
#783=ORIENTED_EDGE('',*,*,#145,.T.);
#784=DIRECTION('',(0.,-1.,0.));
#785=VECTOR('',#784,1.);
#786=CARTESIAN_POINT('',(-51.,41.275,-51.));
#787=LINE('',#786,#785);
#788=CARTESIAN_POINT('',(-51.,41.275,-51.));
#789=VERTEX_POINT('',#788);
#790=EDGE_CURVE('E398',#789,#47,#787,.T.);
#791=ORIENTED_EDGE('',*,*,#790,.F.);
#792=DIRECTION('',(1.,0.,0.));
#793=VECTOR('',#792,1.);
#794=CARTESIAN_POINT('',(-55.,41.275,-51.));
#795=LINE('',#794,#793);
#796=EDGE_CURVE('E384',#287,#789,#795,.T.);
#797=ORIENTED_EDGE('',*,*,#796,.F.);
#798=ORIENTED_EDGE('',*,*,#288,.T.);
#799=EDGE_LOOP('',(#783,#791,#797,#798));
#800=FACE_BOUND('',#799,.T.);
#801=ADVANCED_FACE('F614',(#800),#782,.F.);
#802=CARTESIAN_POINT('',(-51.,41.275,-55.));
#803=DIRECTION('',(-1.,0.,0.));
#804=DIRECTION('',(0.,0.,1.));
#805=AXIS2_PLACEMENT_3D('',#802,#803,#804);
#806=PLANE('',#805);
#807=ORIENTED_EDGE('',*,*,#48,.T.);
#808=ORIENTED_EDGE('',*,*,#265,.F.);
#809=DIRECTION('',(0.,0.,-1.));
#810=VECTOR('',#809,1.);
#811=CARTESIAN_POINT('',(-51.,41.275,-55.));
#812=LINE('',#811,#810);
#813=EDGE_CURVE('E387',#789,#258,#812,.T.);
#814=ORIENTED_EDGE('',*,*,#813,.F.);
#815=ORIENTED_EDGE('',*,*,#790,.T.);
#816=EDGE_LOOP('',(#807,#808,#814,#815));
#817=FACE_BOUND('',#816,.T.);
#818=ADVANCED_FACE('F619',(#817),#806,.F.);
#819=CARTESIAN_POINT('',(-51.,41.275,55.));
#820=DIRECTION('',(-1.,0.,0.));
#821=DIRECTION('',(0.,0.,1.));
#822=AXIS2_PLACEMENT_3D('',#819,#820,#821);
#823=PLANE('',#822);
#824=ORIENTED_EDGE('',*,*,#114,.T.);
#825=DIRECTION('',(0.,-1.,0.));
#826=VECTOR('',#825,1.);
#827=CARTESIAN_POINT('',(-51.,41.275,51.));
#828=LINE('',#827,#826);
#829=CARTESIAN_POINT('',(-51.,41.275,51.));
#830=VERTEX_POINT('',#829);
#831=EDGE_CURVE('E365',#830,#105,#828,.T.);
#832=ORIENTED_EDGE('',*,*,#831,.F.);
#833=DIRECTION('',(0.,0.,-1.));
#834=VECTOR('',#833,1.);
#835=CARTESIAN_POINT('',(-51.,41.275,55.));
#836=LINE('',#835,#834);
#837=EDGE_CURVE('E376',#343,#830,#836,.T.);
#838=ORIENTED_EDGE('',*,*,#837,.F.);
#839=ORIENTED_EDGE('',*,*,#344,.T.);
#840=EDGE_LOOP('',(#824,#832,#838,#839));
#841=FACE_BOUND('',#840,.T.);
#842=ADVANCED_FACE('F585',(#841),#823,.F.);
#843=CARTESIAN_POINT('',(-55.,41.275,51.));
#844=DIRECTION('',(0.,0.,1.));
#845=DIRECTION('',(1.,0.,0.));
#846=AXIS2_PLACEMENT_3D('',#843,#844,#845);
#847=PLANE('',#846);
#848=ORIENTED_EDGE('',*,*,#131,.T.);
#849=ORIENTED_EDGE('',*,*,#302,.F.);
#850=DIRECTION('',(-1.,0.,0.));
#851=VECTOR('',#850,1.);
#852=CARTESIAN_POINT('',(-55.,41.275,51.));
#853=LINE('',#852,#851);
#854=EDGE_CURVE('E371',#830,#295,#853,.T.);
#855=ORIENTED_EDGE('',*,*,#854,.F.);
#856=ORIENTED_EDGE('',*,*,#831,.T.);
#857=EDGE_LOOP('',(#848,#849,#855,#856));
#858=FACE_BOUND('',#857,.T.);
#859=ADVANCED_FACE('F587',(#858),#847,.F.);
#860=CARTESIAN_POINT('',(55.,41.275,51.));
#861=DIRECTION('',(0.,0.,1.));
#862=DIRECTION('',(1.,0.,0.));
#863=AXIS2_PLACEMENT_3D('',#860,#861,#862);
#864=PLANE('',#863);
#865=ORIENTED_EDGE('',*,*,#81,.T.);
#866=DIRECTION('',(0.,-1.,0.));
#867=VECTOR('',#866,1.);
#868=CARTESIAN_POINT('',(51.,41.275,51.));
#869=LINE('',#868,#867);
#870=CARTESIAN_POINT('',(51.,41.275,51.));
#871=VERTEX_POINT('',#870);
#872=EDGE_CURVE('E344',#871,#72,#869,.T.);
#873=ORIENTED_EDGE('',*,*,#872,.F.);
#874=DIRECTION('',(-1.,0.,0.));
#875=VECTOR('',#874,1.);
#876=CARTESIAN_POINT('',(55.,41.275,51.));
#877=LINE('',#876,#875);
#878=EDGE_CURVE('E355',#166,#871,#877,.T.);
#879=ORIENTED_EDGE('',*,*,#878,.F.);
#880=ORIENTED_EDGE('',*,*,#167,.T.);
#881=EDGE_LOOP('',(#865,#873,#879,#880));
#882=FACE_BOUND('',#881,.T.);
#883=ADVANCED_FACE('F594',(#882),#864,.F.);
#884=CARTESIAN_POINT('',(51.,41.275,55.));
#885=DIRECTION('',(1.,0.,0.));
#886=DIRECTION('',(0.,0.,-1.));
#887=AXIS2_PLACEMENT_3D('',#884,#885,#886);
#888=PLANE('',#887);
#889=ORIENTED_EDGE('',*,*,#98,.T.);
#890=ORIENTED_EDGE('',*,*,#358,.F.);
#891=DIRECTION('',(0.,0.,1.));
#892=VECTOR('',#891,1.);
#893=CARTESIAN_POINT('',(51.,41.275,55.));
#894=LINE('',#893,#892);
#895=EDGE_CURVE('E350',#871,#351,#894,.T.);
#896=ORIENTED_EDGE('',*,*,#895,.F.);
#897=ORIENTED_EDGE('',*,*,#872,.T.);
#898=EDGE_LOOP('',(#889,#890,#896,#897));
#899=FACE_BOUND('',#898,.T.);
#900=ADVANCED_FACE('F591',(#899),#888,.F.);
#901=CARTESIAN_POINT('',(51.,41.275,-55.));
#902=DIRECTION('',(1.,0.,0.));
#903=DIRECTION('',(0.,0.,-1.));
#904=AXIS2_PLACEMENT_3D('',#901,#902,#903);
#905=PLANE('',#904);
#906=ORIENTED_EDGE('',*,*,#32,.T.);
#907=DIRECTION('',(0.,-1.,0.));
#908=VECTOR('',#907,1.);
#909=CARTESIAN_POINT('',(51.,41.275,-51.));
#910=LINE('',#909,#908);
#911=CARTESIAN_POINT('',(51.,41.275,-51.));
#912=VERTEX_POINT('',#911);
#913=EDGE_CURVE('E323',#912,#31,#910,.T.);
#914=ORIENTED_EDGE('',*,*,#913,.F.);
#915=DIRECTION('',(0.,0.,1.));
#916=VECTOR('',#915,1.);
#917=CARTESIAN_POINT('',(51.,41.275,-55.));
#918=LINE('',#917,#916);
#919=EDGE_CURVE('E334',#256,#912,#918,.T.);
#920=ORIENTED_EDGE('',*,*,#919,.F.);
#921=ORIENTED_EDGE('',*,*,#272,.T.);
#922=EDGE_LOOP('',(#906,#914,#920,#921));
#923=FACE_BOUND('',#922,.T.);
#924=ADVANCED_FACE('F604',(#923),#905,.F.);
#925=CARTESIAN_POINT('',(55.,41.275,-51.));
#926=DIRECTION('',(0.,0.,-1.));
#927=DIRECTION('',(-1.,0.,0.));
#928=AXIS2_PLACEMENT_3D('',#925,#926,#927);
#929=PLANE('',#928);
#930=ORIENTED_EDGE('',*,*,#65,.T.);
#931=ORIENTED_EDGE('',*,*,#181,.F.);
#932=DIRECTION('',(1.,0.,0.));
#933=VECTOR('',#932,1.);
#934=CARTESIAN_POINT('',(55.,41.275,-51.));
#935=LINE('',#934,#933);
#936=EDGE_CURVE('E329',#912,#174,#935,.T.);
#937=ORIENTED_EDGE('',*,*,#936,.F.);
#938=ORIENTED_EDGE('',*,*,#913,.T.);
#939=EDGE_LOOP('',(#930,#931,#937,#938));
#940=FACE_BOUND('',#939,.T.);
#941=ADVANCED_FACE('F600',(#940),#929,.F.);
#942=CARTESIAN_POINT('',(0.,41.275,0.));
#943=DIRECTION('',(0.,1.,0.));
#944=DIRECTION('',(0.,0.,1.));
#945=AXIS2_PLACEMENT_3D('',#942,#943,#944);
#946=PLANE('',#945);
#947=DIRECTION('',(0.,0.,-1.));
#948=VECTOR('',#947,1.);
#949=CARTESIAN_POINT('',(-49.,41.275,-49.));
#950=LINE('',#949,#948);
#951=CARTESIAN_POINT('',(-49.,41.275,-29.95));
#952=VERTEX_POINT('',#951);
#953=CARTESIAN_POINT('',(-49.,41.275,-49.));
#954=VERTEX_POINT('',#953);
#955=EDGE_CURVE('E247',#952,#954,#950,.T.);
#956=ORIENTED_EDGE('',*,*,#955,.F.);
#957=DIRECTION('',(-1.,0.,0.));
#958=VECTOR('',#957,1.);
#959=CARTESIAN_POINT('',(-49.,41.275,-29.95));
#960=LINE('',#959,#958);
#961=CARTESIAN_POINT('',(-29.95,41.275,-29.95));
#962=VERTEX_POINT('',#961);
#963=EDGE_CURVE('E54',#962,#952,#960,.T.);
#964=ORIENTED_EDGE('',*,*,#963,.F.);
#965=DIRECTION('',(0.,0.,1.));
#966=VECTOR('',#965,1.);
#967=CARTESIAN_POINT('',(-29.95,41.275,-49.));
#968=LINE('',#967,#966);
#969=CARTESIAN_POINT('',(-29.95,41.275,-49.));
#970=VERTEX_POINT('',#969);
#971=EDGE_CURVE('E254',#970,#962,#968,.T.);
#972=ORIENTED_EDGE('',*,*,#971,.F.);
#973=DIRECTION('',(1.,0.,0.));
#974=VECTOR('',#973,1.);
#975=CARTESIAN_POINT('',(-49.,41.275,-49.));
#976=LINE('',#975,#974);
#977=EDGE_CURVE('E238',#954,#970,#976,.T.);
#978=ORIENTED_EDGE('',*,*,#977,.F.);
#979=EDGE_LOOP('',(#956,#964,#972,#978));
#980=FACE_BOUND('',#979,.T.);
#981=ORIENTED_EDGE('',*,*,#296,.F.);
#982=ORIENTED_EDGE('',*,*,#796,.T.);
#983=ORIENTED_EDGE('',*,*,#813,.T.);
#984=ORIENTED_EDGE('',*,*,#259,.F.);
#985=ORIENTED_EDGE('',*,*,#919,.T.);
#986=ORIENTED_EDGE('',*,*,#936,.T.);
#987=ORIENTED_EDGE('',*,*,#175,.F.);
#988=ORIENTED_EDGE('',*,*,#878,.T.);
#989=ORIENTED_EDGE('',*,*,#895,.T.);
#990=ORIENTED_EDGE('',*,*,#352,.F.);
#991=ORIENTED_EDGE('',*,*,#837,.T.);
#992=ORIENTED_EDGE('',*,*,#854,.T.);
#993=EDGE_LOOP('',(#981,#982,#983,#984,#985,#986,#987,#988,#989,#990,#991,#992));
#994=FACE_BOUND('',#993,.T.);
#995=ADVANCED_FACE('F251',(#980,#994),#946,.F.);
#996=CARTESIAN_POINT('',(0.,50.8,0.));
#997=DIRECTION('',(0.,1.,0.));
#998=DIRECTION('',(0.,0.,1.));
#999=AXIS2_PLACEMENT_3D('',#996,#997,#998);
#1000=PLANE('',#999);
#1001=DIRECTION('',(0.,0.,1.));
#1002=VECTOR('',#1001,1.);
#1003=CARTESIAN_POINT('',(-52.,50.8,-52.));
#1004=LINE('',#1003,#1002);
#1005=CARTESIAN_POINT('',(-52.,50.8,-52.));
#1006=VERTEX_POINT('',#1005);
#1007=CARTESIAN_POINT('',(-52.,50.8,52.));
#1008=VERTEX_POINT('',#1007);
#1009=EDGE_CURVE('E264',#1006,#1008,#1004,.T.);
#1010=ORIENTED_EDGE('',*,*,#1009,.F.);
#1011=DIRECTION('',(-1.,0.,0.));
#1012=VECTOR('',#1011,1.);
#1013=CARTESIAN_POINT('',(-52.,50.8,-52.));
#1014=LINE('',#1013,#1012);
#1015=CARTESIAN_POINT('',(23.1,50.8,-52.));
#1016=VERTEX_POINT('',#1015);
#1017=EDGE_CURVE('E269',#1016,#1006,#1014,.T.);
#1018=ORIENTED_EDGE('',*,*,#1017,.F.);
#1019=DIRECTION('',(0.,0.,-1.));
#1020=VECTOR('',#1019,1.);
#1021=CARTESIAN_POINT('',(23.1,50.8,-52.));
#1022=LINE('',#1021,#1020);
#1023=CARTESIAN_POINT('',(23.1,50.8,52.));
#1024=VERTEX_POINT('',#1023);
#1025=EDGE_CURVE('E283',#1024,#1016,#1022,.T.);
#1026=ORIENTED_EDGE('',*,*,#1025,.F.);
#1027=DIRECTION('',(1.,0.,0.));
#1028=VECTOR('',#1027,1.);
#1029=CARTESIAN_POINT('',(-52.,50.8,52.));
#1030=LINE('',#1029,#1028);
#1031=EDGE_CURVE('E280',#1008,#1024,#1030,.T.);
#1032=ORIENTED_EDGE('',*,*,#1031,.F.);
#1033=EDGE_LOOP('',(#1010,#1018,#1026,#1032));
#1034=FACE_BOUND('',#1033,.T.);
#1035=ORIENTED_EDGE('',*,*,#327,.T.);
#1036=ORIENTED_EDGE('',*,*,#374,.T.);
#1037=ORIENTED_EDGE('',*,*,#210,.T.);
#1038=ORIENTED_EDGE('',*,*,#240,.T.);
#1039=EDGE_LOOP('',(#1035,#1036,#1037,#1038));
#1040=FACE_BOUND('',#1039,.T.);
#1041=ADVANCED_FACE('F528',(#1034,#1040),#1000,.T.);
#1042=CARTESIAN_POINT('',(-52.,44.45,-52.));
#1043=DIRECTION('',(-1.,0.,0.));
#1044=DIRECTION('',(0.,0.,1.));
#1045=AXIS2_PLACEMENT_3D('',#1042,#1043,#1044);
#1046=PLANE('',#1045);
#1047=ORIENTED_EDGE('',*,*,#1009,.T.);
#1048=DIRECTION('',(0.,1.,0.));
#1049=VECTOR('',#1048,1.);
#1050=CARTESIAN_POINT('',(-52.,44.45,52.));
#1051=LINE('',#1050,#1049);
#1052=CARTESIAN_POINT('',(-52.,44.45,52.));
#1053=VERTEX_POINT('',#1052);
#1054=EDGE_CURVE('E278',#1053,#1008,#1051,.T.);
#1055=ORIENTED_EDGE('',*,*,#1054,.F.);
#1056=DIRECTION('',(0.,0.,1.));
#1057=VECTOR('',#1056,1.);
#1058=CARTESIAN_POINT('',(-52.,44.45,-52.));
#1059=LINE('',#1058,#1057);
#1060=CARTESIAN_POINT('',(-52.,44.45,-52.));
#1061=VERTEX_POINT('',#1060);
#1062=EDGE_CURVE('E265',#1061,#1053,#1059,.T.);
#1063=ORIENTED_EDGE('',*,*,#1062,.F.);
#1064=DIRECTION('',(0.,1.,0.));
#1065=VECTOR('',#1064,1.);
#1066=CARTESIAN_POINT('',(-52.,44.45,-52.));
#1067=LINE('',#1066,#1065);
#1068=EDGE_CURVE('E288',#1061,#1006,#1067,.T.);
#1069=ORIENTED_EDGE('',*,*,#1068,.T.);
#1070=EDGE_LOOP('',(#1047,#1055,#1063,#1069));
#1071=FACE_BOUND('',#1070,.T.);
#1072=ADVANCED_FACE('F893',(#1071),#1046,.F.);
#1073=CARTESIAN_POINT('',(-52.,44.45,-52.));
#1074=DIRECTION('',(0.,0.,-1.));
#1075=DIRECTION('',(-1.,0.,0.));
#1076=AXIS2_PLACEMENT_3D('',#1073,#1074,#1075);
#1077=PLANE('',#1076);
#1078=ORIENTED_EDGE('',*,*,#1017,.T.);
#1079=ORIENTED_EDGE('',*,*,#1068,.F.);
#1080=DIRECTION('',(-1.,0.,0.));
#1081=VECTOR('',#1080,1.);
#1082=CARTESIAN_POINT('',(-52.,44.45,-52.));
#1083=LINE('',#1082,#1081);
#1084=CARTESIAN_POINT('',(23.1,44.45,-52.));
#1085=VERTEX_POINT('',#1084);
#1086=EDGE_CURVE('E275',#1085,#1061,#1083,.T.);
#1087=ORIENTED_EDGE('',*,*,#1086,.F.);
#1088=DIRECTION('',(0.,1.,0.));
#1089=VECTOR('',#1088,1.);
#1090=CARTESIAN_POINT('',(23.1,44.45,-52.));
#1091=LINE('',#1090,#1089);
#1092=EDGE_CURVE('E291',#1085,#1016,#1091,.T.);
#1093=ORIENTED_EDGE('',*,*,#1092,.T.);
#1094=EDGE_LOOP('',(#1078,#1079,#1087,#1093));
#1095=FACE_BOUND('',#1094,.T.);
#1096=ADVANCED_FACE('F902',(#1095),#1077,.F.);
#1097=CARTESIAN_POINT('',(23.1,44.45,-52.));
#1098=DIRECTION('',(1.,0.,0.));
#1099=DIRECTION('',(0.,0.,-1.));
#1100=AXIS2_PLACEMENT_3D('',#1097,#1098,#1099);
#1101=PLANE('',#1100);
#1102=ORIENTED_EDGE('',*,*,#1025,.T.);
#1103=ORIENTED_EDGE('',*,*,#1092,.F.);
#1104=DIRECTION('',(0.,0.,-1.));
#1105=VECTOR('',#1104,1.);
#1106=CARTESIAN_POINT('',(23.1,44.45,-52.));
#1107=LINE('',#1106,#1105);
#1108=CARTESIAN_POINT('',(23.1,44.45,52.));
#1109=VERTEX_POINT('',#1108);
#1110=EDGE_CURVE('E272',#1109,#1085,#1107,.T.);
#1111=ORIENTED_EDGE('',*,*,#1110,.F.);
#1112=DIRECTION('',(0.,1.,0.));
#1113=VECTOR('',#1112,1.);
#1114=CARTESIAN_POINT('',(23.1,44.45,52.));
#1115=LINE('',#1114,#1113);
#1116=EDGE_CURVE('E293',#1109,#1024,#1115,.T.);
#1117=ORIENTED_EDGE('',*,*,#1116,.T.);
#1118=EDGE_LOOP('',(#1102,#1103,#1111,#1117));
#1119=FACE_BOUND('',#1118,.T.);
#1120=ADVANCED_FACE('F911',(#1119),#1101,.F.);
#1121=CARTESIAN_POINT('',(-52.,44.45,52.));
#1122=DIRECTION('',(0.,0.,1.));
#1123=DIRECTION('',(1.,0.,0.));
#1124=AXIS2_PLACEMENT_3D('',#1121,#1122,#1123);
#1125=PLANE('',#1124);
#1126=ORIENTED_EDGE('',*,*,#1031,.T.);
#1127=ORIENTED_EDGE('',*,*,#1116,.F.);
#1128=DIRECTION('',(1.,0.,0.));
#1129=VECTOR('',#1128,1.);
#1130=CARTESIAN_POINT('',(-52.,44.45,52.));
#1131=LINE('',#1130,#1129);
#1132=EDGE_CURVE('E268',#1053,#1109,#1131,.T.);
#1133=ORIENTED_EDGE('',*,*,#1132,.F.);
#1134=ORIENTED_EDGE('',*,*,#1054,.T.);
#1135=EDGE_LOOP('',(#1126,#1127,#1133,#1134));
#1136=FACE_BOUND('',#1135,.T.);
#1137=ADVANCED_FACE('F920',(#1136),#1125,.F.);
#1138=CARTESIAN_POINT('',(0.,44.45,0.));
#1139=DIRECTION('',(0.,1.,0.));
#1140=DIRECTION('',(0.,0.,1.));
#1141=AXIS2_PLACEMENT_3D('',#1138,#1139,#1140);
#1142=PLANE('',#1141);
#1143=DIRECTION('',(1.,0.,0.));
#1144=VECTOR('',#1143,1.);
#1145=CARTESIAN_POINT('',(-49.,44.45,-29.95));
#1146=LINE('',#1145,#1144);
#1147=CARTESIAN_POINT('',(-49.,44.45,-29.95));
#1148=VERTEX_POINT('',#1147);
#1149=CARTESIAN_POINT('',(-29.95,44.45,-29.95));
#1150=VERTEX_POINT('',#1149);
#1151=EDGE_CURVE('E996',#1148,#1150,#1146,.T.);
#1152=ORIENTED_EDGE('',*,*,#1151,.F.);
#1153=DIRECTION('',(0.,0.,1.));
#1154=VECTOR('',#1153,1.);
#1155=CARTESIAN_POINT('',(-49.,44.45,-49.));
#1156=LINE('',#1155,#1154);
#1157=CARTESIAN_POINT('',(-49.,44.45,-49.));
#1158=VERTEX_POINT('',#1157);
#1159=EDGE_CURVE('E256',#1158,#1148,#1156,.T.);
#1160=ORIENTED_EDGE('',*,*,#1159,.F.);
#1161=DIRECTION('',(-1.,0.,0.));
#1162=VECTOR('',#1161,1.);
#1163=CARTESIAN_POINT('',(-49.,44.45,-49.));
#1164=LINE('',#1163,#1162);
#1165=CARTESIAN_POINT('',(-29.95,44.45,-49.));
#1166=VERTEX_POINT('',#1165);
#1167=EDGE_CURVE('E62',#1166,#1158,#1164,.T.);
#1168=ORIENTED_EDGE('',*,*,#1167,.F.);
#1169=DIRECTION('',(0.,0.,-1.));
#1170=VECTOR('',#1169,1.);
#1171=CARTESIAN_POINT('',(-29.95,44.45,-49.));
#1172=LINE('',#1171,#1170);
#1173=EDGE_CURVE('E994',#1150,#1166,#1172,.T.);
#1174=ORIENTED_EDGE('',*,*,#1173,.F.);
#1175=EDGE_LOOP('',(#1152,#1160,#1168,#1174));
#1176=FACE_BOUND('',#1175,.T.);
#1177=ORIENTED_EDGE('',*,*,#1062,.T.);
#1178=ORIENTED_EDGE('',*,*,#1132,.T.);
#1179=ORIENTED_EDGE('',*,*,#1110,.T.);
#1180=ORIENTED_EDGE('',*,*,#1086,.T.);
#1181=EDGE_LOOP('',(#1177,#1178,#1179,#1180));
#1182=FACE_BOUND('',#1181,.T.);
#1183=ADVANCED_FACE('F929',(#1176,#1182),#1142,.T.);
#1184=CARTESIAN_POINT('',(-49.,-8.001,-29.95));
#1185=DIRECTION('',(0.,0.,1.));
#1186=DIRECTION('',(1.,0.,0.));
#1187=AXIS2_PLACEMENT_3D('',#1184,#1185,#1186);
#1188=PLANE('',#1187);
#1189=ORIENTED_EDGE('',*,*,#963,.T.);
#1190=DIRECTION('',(0.,1.,0.));
#1191=VECTOR('',#1190,1.);
#1192=CARTESIAN_POINT('',(-49.,-8.001,-29.95));
#1193=LINE('',#1192,#1191);
#1194=EDGE_CURVE('E243',#952,#1148,#1193,.T.);
#1195=ORIENTED_EDGE('',*,*,#1194,.T.);
#1196=ORIENTED_EDGE('',*,*,#1151,.T.);
#1197=DIRECTION('',(0.,1.,0.));
#1198=VECTOR('',#1197,1.);
#1199=CARTESIAN_POINT('',(-29.95,-8.001,-29.95));
#1200=LINE('',#1199,#1198);
#1201=EDGE_CURVE('E261',#962,#1150,#1200,.T.);
#1202=ORIENTED_EDGE('',*,*,#1201,.F.);
#1203=EDGE_LOOP('',(#1189,#1195,#1196,#1202));
#1204=FACE_BOUND('',#1203,.T.);
#1205=ADVANCED_FACE('F943',(#1204),#1188,.F.);
#1206=CARTESIAN_POINT('',(-29.95,-8.001,-49.));
#1207=DIRECTION('',(1.,0.,0.));
#1208=DIRECTION('',(0.,0.,-1.));
#1209=AXIS2_PLACEMENT_3D('',#1206,#1207,#1208);
#1210=PLANE('',#1209);
#1211=ORIENTED_EDGE('',*,*,#971,.T.);
#1212=ORIENTED_EDGE('',*,*,#1201,.T.);
#1213=ORIENTED_EDGE('',*,*,#1173,.T.);
#1214=DIRECTION('',(0.,1.,0.));
#1215=VECTOR('',#1214,1.);
#1216=CARTESIAN_POINT('',(-29.95,-8.001,-49.));
#1217=LINE('',#1216,#1215);
#1218=EDGE_CURVE('E244',#970,#1166,#1217,.T.);
#1219=ORIENTED_EDGE('',*,*,#1218,.F.);
#1220=EDGE_LOOP('',(#1211,#1212,#1213,#1219));
#1221=FACE_BOUND('',#1220,.T.);
#1222=ADVANCED_FACE('F952',(#1221),#1210,.F.);
#1223=CARTESIAN_POINT('',(-49.,-8.001,-49.));
#1224=DIRECTION('',(0.,0.,-1.));
#1225=DIRECTION('',(-1.,0.,0.));
#1226=AXIS2_PLACEMENT_3D('',#1223,#1224,#1225);
#1227=PLANE('',#1226);
#1228=ORIENTED_EDGE('',*,*,#977,.T.);
#1229=ORIENTED_EDGE('',*,*,#1218,.T.);
#1230=ORIENTED_EDGE('',*,*,#1167,.T.);
#1231=DIRECTION('',(0.,1.,0.));
#1232=VECTOR('',#1231,1.);
#1233=CARTESIAN_POINT('',(-49.,-8.001,-49.));
#1234=LINE('',#1233,#1232);
#1235=EDGE_CURVE('E234',#954,#1158,#1234,.T.);
#1236=ORIENTED_EDGE('',*,*,#1235,.F.);
#1237=EDGE_LOOP('',(#1228,#1229,#1230,#1236));
#1238=FACE_BOUND('',#1237,.T.);
#1239=ADVANCED_FACE('F236',(#1238),#1227,.F.);
#1240=CARTESIAN_POINT('',(-49.,-8.001,-49.));
#1241=DIRECTION('',(-1.,0.,0.));
#1242=DIRECTION('',(0.,0.,1.));
#1243=AXIS2_PLACEMENT_3D('',#1240,#1241,#1242);
#1244=PLANE('',#1243);
#1245=ORIENTED_EDGE('',*,*,#955,.T.);
#1246=ORIENTED_EDGE('',*,*,#1235,.T.);
#1247=ORIENTED_EDGE('',*,*,#1159,.T.);
#1248=ORIENTED_EDGE('',*,*,#1194,.F.);
#1249=EDGE_LOOP('',(#1245,#1246,#1247,#1248));
#1250=FACE_BOUND('',#1249,.T.);
#1251=ADVANCED_FACE('F248',(#1250),#1244,.F.);
#1252=CLOSED_SHELL('',(#58,#91,#124,#155,#220,#276,#332,#379,#469,#500,#524,#548,#565,#621,#633,
#645,#657,#669,#700,#724,#748,#765,#777,#801,#818,#842,#859,#883,#900,#924,#941,#995,#1041,
#1072,#1096,#1120,#1137,#1183,#1205,#1222,#1239,#1251));
#1253=MANIFOLD_SOLID_BREP('B2',#1252);
#1254=ADVANCED_BREP_SHAPE_REPRESENTATION('',(#18,#1253),#14);
#1255=SHAPE_DEFINITION_REPRESENTATION(#9,#1254);
ENDSEC;
END-ISO-10303-21;
